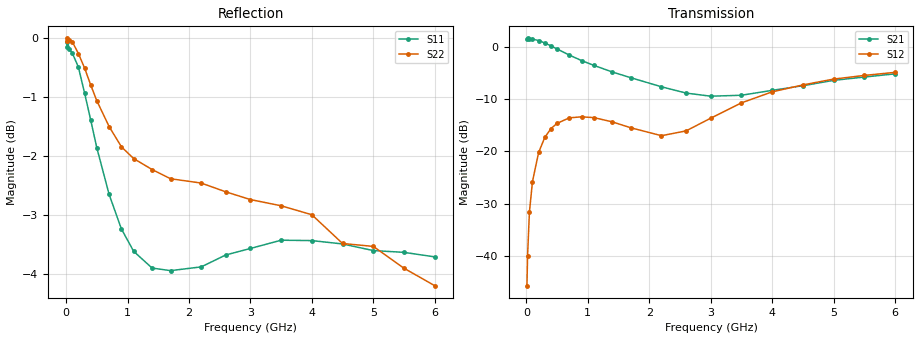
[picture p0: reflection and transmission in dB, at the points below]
! Infineon Technologies  Discrete & RF Semiconductors
! BFS17W
! Si NPN RF Bipolar Junction Transistor in SOT323
! VCE = 1.75 V  IC = 0.3 mA
! Common Emitter S-Parameters:  August  1999
# GHz  S  MA  R  50
!  f  S11  S21  S12  S22
! GHz  MAG  ANG  MAG  ANG  MAG  ANG  MAG  ANG
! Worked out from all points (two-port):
!   36 points, 10 MHz to 6 GHz, reference 50 ohm
!   highest |S21| = 1.58 dB at 20 MHz (marker M1); lowest = -9.5 dB at 3 GHz (marker M2)
!   |S21| within 3 dB of the highest: start of sweep to 665 MHz
!   lowest |S11| = -3.9 dB at 1.7 GHz (marker M3), VSWR 4.48, Z = 11.2 - j2.32 ohm
!   |S11| at or under -10 dB: nowhere
!   |S22| runs from -4.2 to 0.0 dB; largest |S21 - S12| = 1.2
!   S11 on the Smith chart (normalised r, x): 10 MHz: 29, -51; 300 MHz: 0.27, -2.01; 700 MHz: 0.24, -0.75; 1.4 GHz: 0.23, -0.18; 3 GHz: 0.23, +0.39; 6 GHz: 0.49, +1.09
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0.01  0.9836 -1.7  1.189 179.2  0.0052 88.3  0.9999 -0.1
0.02  0.9935 -3.9  1.199 176.9  0.0099 84.1  0.9948 -1.0
0.05  0.9795 -9.1  1.194 172.0  0.0261 84.7  0.9972 -3.0
0.1  0.9719 -17.9  1.177 164.4  0.0514 78.4  0.9935 -5.9
0.2  0.9452 -35.8  1.144 148.6  0.0974 67.8  0.9707 -11.3
0.3  0.8989 -52.2  1.084 134.3  0.1355 57.7  0.9438 -16.1
0.4  0.8527 -67.2  1.017 121.0  0.1647 48.8  0.913 -20.5
0.5  0.8074 -80.7  0.949 109.7  0.1848 41.3  0.8851 -24.1
0.7  0.7372 -104.1  0.83 90.2  0.2087 29.9  0.8417 -30.7
0.9  0.6891 -123.1  0.735 75.0  0.2134 21.5  0.8091 -36.7
1.1  0.6596 -139.1  0.662 62.3  0.2098 15.8  0.7906 -42.6
1.4  0.6384 -158.5  0.572 48.1  0.1909 10.9  0.7739 -51.8
1.7  0.6352 -174.4  0.505 37.6  0.1678 11.7  0.7601 -61.7
2.2  0.6399 163.8  0.413 27.5  0.1409 27.1  0.7537 -78.2
2.6  0.655 148.9  0.36 25.7  0.1566 46.1  0.7409 -92.1
3  0.6633 135.5  0.336 28.4  0.2069 56.1  0.7298 -105.4
3.5  0.6741 121.0  0.343 33.5  0.2899 57.1  0.721 -122.3
4  0.6736 108.9  0.382 35.6  0.3695 51.8  0.7085 -139.7
4.5  0.6692 98.7  0.423 34.3  0.4304 45.1  0.6698 -155.3
5  0.6606 90.8  0.476 31.1  0.4893 38.5  0.666 -168.3
5.5  0.6583 84.0  0.512 26.9  0.5304 32.0  0.6382 178.2
6  0.6525 78.7  0.549 22.4  0.5675 26.1  0.6168 166.6
